VERSION 5.7 ;
BUSBITCHARS "[]" ;
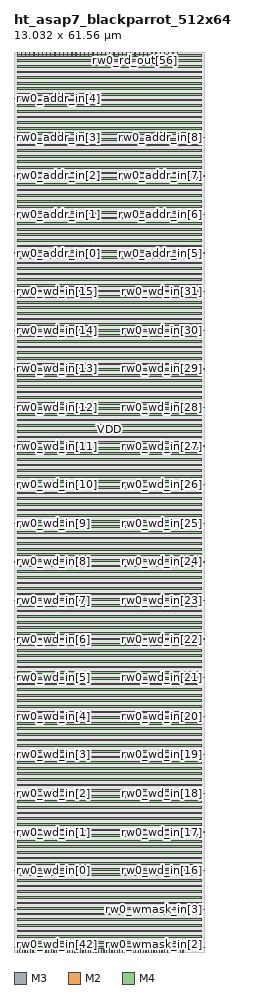
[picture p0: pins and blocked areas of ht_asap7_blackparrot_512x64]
MACRO ht_asap7_blackparrot_512x64
  FOREIGN ht_asap7_blackparrot_512x64 0 0 ;
  SYMMETRY X Y R90 ;
  SIZE 13.032 BY 61.560 ;
  CLASS BLOCK ;
  PIN rw0_wmask_in[0]
    DIRECTION INPUT ;
    USE SIGNAL ;
    SHAPE ABUTMENT ;
    PORT
      LAYER M3 ;
      RECT 0.000 0.276 0.072 0.300 ;
    END
  END rw0_wmask_in[0]
  PIN rw0_wmask_in[1]
    DIRECTION INPUT ;
    USE SIGNAL ;
    SHAPE ABUTMENT ;
    PORT
      LAYER M3 ;
      RECT 0.000 2.916 0.072 2.940 ;
    END
  END rw0_wmask_in[1]
  PIN rw0_wmask_in[2]
    DIRECTION INPUT ;
    USE SIGNAL ;
    SHAPE ABUTMENT ;
    PORT
      LAYER M3 ;
      RECT 12.960 0.276 13.032 0.300 ;
    END
  END rw0_wmask_in[2]
  PIN rw0_wmask_in[3]
    DIRECTION INPUT ;
    USE SIGNAL ;
    SHAPE ABUTMENT ;
    PORT
      LAYER M3 ;
      RECT 12.960 2.916 13.032 2.940 ;
    END
  END rw0_wmask_in[3]
  PIN rw0_wmask_in[4]
    DIRECTION INPUT ;
    USE SIGNAL ;
    SHAPE ABUTMENT ;
    PORT
      LAYER M2 ;
      RECT 0.207 61.290 0.225 61.560 ;
    END
  END rw0_wmask_in[4]
  PIN rw0_wmask_in[5]
    DIRECTION INPUT ;
    USE SIGNAL ;
    SHAPE ABUTMENT ;
    PORT
      LAYER M2 ;
      RECT 0.495 61.290 0.513 61.560 ;
    END
  END rw0_wmask_in[5]
  PIN rw0_wmask_in[6]
    DIRECTION INPUT ;
    USE SIGNAL ;
    SHAPE ABUTMENT ;
    PORT
      LAYER M2 ;
      RECT 0.783 61.290 0.801 61.560 ;
    END
  END rw0_wmask_in[6]
  PIN rw0_wmask_in[7]
    DIRECTION INPUT ;
    USE SIGNAL ;
    SHAPE ABUTMENT ;
    PORT
      LAYER M2 ;
      RECT 1.071 61.290 1.089 61.560 ;
    END
  END rw0_wmask_in[7]
  PIN rw0_wd_in[0]
    DIRECTION INPUT ;
    USE SIGNAL ;
    SHAPE ABUTMENT ;
    PORT
      LAYER M3 ;
      RECT 0.000 5.556 0.072 5.580 ;
    END
  END rw0_wd_in[0]
  PIN rw0_wd_in[1]
    DIRECTION INPUT ;
    USE SIGNAL ;
    SHAPE ABUTMENT ;
    PORT
      LAYER M3 ;
      RECT 0.000 8.196 0.072 8.220 ;
    END
  END rw0_wd_in[1]
  PIN rw0_wd_in[2]
    DIRECTION INPUT ;
    USE SIGNAL ;
    SHAPE ABUTMENT ;
    PORT
      LAYER M3 ;
      RECT 0.000 10.836 0.072 10.860 ;
    END
  END rw0_wd_in[2]
  PIN rw0_wd_in[3]
    DIRECTION INPUT ;
    USE SIGNAL ;
    SHAPE ABUTMENT ;
    PORT
      LAYER M3 ;
      RECT 0.000 13.476 0.072 13.500 ;
    END
  END rw0_wd_in[3]
  PIN rw0_wd_in[4]
    DIRECTION INPUT ;
    USE SIGNAL ;
    SHAPE ABUTMENT ;
    PORT
      LAYER M3 ;
      RECT 0.000 16.116 0.072 16.140 ;
    END
  END rw0_wd_in[4]
  PIN rw0_wd_in[5]
    DIRECTION INPUT ;
    USE SIGNAL ;
    SHAPE ABUTMENT ;
    PORT
      LAYER M3 ;
      RECT 0.000 18.756 0.072 18.780 ;
    END
  END rw0_wd_in[5]
  PIN rw0_wd_in[6]
    DIRECTION INPUT ;
    USE SIGNAL ;
    SHAPE ABUTMENT ;
    PORT
      LAYER M3 ;
      RECT 0.000 21.396 0.072 21.420 ;
    END
  END rw0_wd_in[6]
  PIN rw0_wd_in[7]
    DIRECTION INPUT ;
    USE SIGNAL ;
    SHAPE ABUTMENT ;
    PORT
      LAYER M3 ;
      RECT 0.000 24.036 0.072 24.060 ;
    END
  END rw0_wd_in[7]
  PIN rw0_wd_in[8]
    DIRECTION INPUT ;
    USE SIGNAL ;
    SHAPE ABUTMENT ;
    PORT
      LAYER M3 ;
      RECT 0.000 26.676 0.072 26.700 ;
    END
  END rw0_wd_in[8]
  PIN rw0_wd_in[9]
    DIRECTION INPUT ;
    USE SIGNAL ;
    SHAPE ABUTMENT ;
    PORT
      LAYER M3 ;
      RECT 0.000 29.316 0.072 29.340 ;
    END
  END rw0_wd_in[9]
  PIN rw0_wd_in[10]
    DIRECTION INPUT ;
    USE SIGNAL ;
    SHAPE ABUTMENT ;
    PORT
      LAYER M3 ;
      RECT 0.000 31.956 0.072 31.980 ;
    END
  END rw0_wd_in[10]
  PIN rw0_wd_in[11]
    DIRECTION INPUT ;
    USE SIGNAL ;
    SHAPE ABUTMENT ;
    PORT
      LAYER M3 ;
      RECT 0.000 34.596 0.072 34.620 ;
    END
  END rw0_wd_in[11]
  PIN rw0_wd_in[12]
    DIRECTION INPUT ;
    USE SIGNAL ;
    SHAPE ABUTMENT ;
    PORT
      LAYER M3 ;
      RECT 0.000 37.236 0.072 37.260 ;
    END
  END rw0_wd_in[12]
  PIN rw0_wd_in[13]
    DIRECTION INPUT ;
    USE SIGNAL ;
    SHAPE ABUTMENT ;
    PORT
      LAYER M3 ;
      RECT 0.000 39.876 0.072 39.900 ;
    END
  END rw0_wd_in[13]
  PIN rw0_wd_in[14]
    DIRECTION INPUT ;
    USE SIGNAL ;
    SHAPE ABUTMENT ;
    PORT
      LAYER M3 ;
      RECT 0.000 42.516 0.072 42.540 ;
    END
  END rw0_wd_in[14]
  PIN rw0_wd_in[15]
    DIRECTION INPUT ;
    USE SIGNAL ;
    SHAPE ABUTMENT ;
    PORT
      LAYER M3 ;
      RECT 0.000 45.156 0.072 45.180 ;
    END
  END rw0_wd_in[15]
  PIN rw0_wd_in[16]
    DIRECTION INPUT ;
    USE SIGNAL ;
    SHAPE ABUTMENT ;
    PORT
      LAYER M3 ;
      RECT 12.960 5.556 13.032 5.580 ;
    END
  END rw0_wd_in[16]
  PIN rw0_wd_in[17]
    DIRECTION INPUT ;
    USE SIGNAL ;
    SHAPE ABUTMENT ;
    PORT
      LAYER M3 ;
      RECT 12.960 8.196 13.032 8.220 ;
    END
  END rw0_wd_in[17]
  PIN rw0_wd_in[18]
    DIRECTION INPUT ;
    USE SIGNAL ;
    SHAPE ABUTMENT ;
    PORT
      LAYER M3 ;
      RECT 12.960 10.836 13.032 10.860 ;
    END
  END rw0_wd_in[18]
  PIN rw0_wd_in[19]
    DIRECTION INPUT ;
    USE SIGNAL ;
    SHAPE ABUTMENT ;
    PORT
      LAYER M3 ;
      RECT 12.960 13.476 13.032 13.500 ;
    END
  END rw0_wd_in[19]
  PIN rw0_wd_in[20]
    DIRECTION INPUT ;
    USE SIGNAL ;
    SHAPE ABUTMENT ;
    PORT
      LAYER M3 ;
      RECT 12.960 16.116 13.032 16.140 ;
    END
  END rw0_wd_in[20]
  PIN rw0_wd_in[21]
    DIRECTION INPUT ;
    USE SIGNAL ;
    SHAPE ABUTMENT ;
    PORT
      LAYER M3 ;
      RECT 12.960 18.756 13.032 18.780 ;
    END
  END rw0_wd_in[21]
  PIN rw0_wd_in[22]
    DIRECTION INPUT ;
    USE SIGNAL ;
    SHAPE ABUTMENT ;
    PORT
      LAYER M3 ;
      RECT 12.960 21.396 13.032 21.420 ;
    END
  END rw0_wd_in[22]
  PIN rw0_wd_in[23]
    DIRECTION INPUT ;
    USE SIGNAL ;
    SHAPE ABUTMENT ;
    PORT
      LAYER M3 ;
      RECT 12.960 24.036 13.032 24.060 ;
    END
  END rw0_wd_in[23]
  PIN rw0_wd_in[24]
    DIRECTION INPUT ;
    USE SIGNAL ;
    SHAPE ABUTMENT ;
    PORT
      LAYER M3 ;
      RECT 12.960 26.676 13.032 26.700 ;
    END
  END rw0_wd_in[24]
  PIN rw0_wd_in[25]
    DIRECTION INPUT ;
    USE SIGNAL ;
    SHAPE ABUTMENT ;
    PORT
      LAYER M3 ;
      RECT 12.960 29.316 13.032 29.340 ;
    END
  END rw0_wd_in[25]
  PIN rw0_wd_in[26]
    DIRECTION INPUT ;
    USE SIGNAL ;
    SHAPE ABUTMENT ;
    PORT
      LAYER M3 ;
      RECT 12.960 31.956 13.032 31.980 ;
    END
  END rw0_wd_in[26]
  PIN rw0_wd_in[27]
    DIRECTION INPUT ;
    USE SIGNAL ;
    SHAPE ABUTMENT ;
    PORT
      LAYER M3 ;
      RECT 12.960 34.596 13.032 34.620 ;
    END
  END rw0_wd_in[27]
  PIN rw0_wd_in[28]
    DIRECTION INPUT ;
    USE SIGNAL ;
    SHAPE ABUTMENT ;
    PORT
      LAYER M3 ;
      RECT 12.960 37.236 13.032 37.260 ;
    END
  END rw0_wd_in[28]
  PIN rw0_wd_in[29]
    DIRECTION INPUT ;
    USE SIGNAL ;
    SHAPE ABUTMENT ;
    PORT
      LAYER M3 ;
      RECT 12.960 39.876 13.032 39.900 ;
    END
  END rw0_wd_in[29]
  PIN rw0_wd_in[30]
    DIRECTION INPUT ;
    USE SIGNAL ;
    SHAPE ABUTMENT ;
    PORT
      LAYER M3 ;
      RECT 12.960 42.516 13.032 42.540 ;
    END
  END rw0_wd_in[30]
  PIN rw0_wd_in[31]
    DIRECTION INPUT ;
    USE SIGNAL ;
    SHAPE ABUTMENT ;
    PORT
      LAYER M3 ;
      RECT 12.960 45.156 13.032 45.180 ;
    END
  END rw0_wd_in[31]
  PIN rw0_wd_in[32]
    DIRECTION INPUT ;
    USE SIGNAL ;
    SHAPE ABUTMENT ;
    PORT
      LAYER M2 ;
      RECT 0.207 0.000 0.225 0.270 ;
    END
  END rw0_wd_in[32]
  PIN rw0_wd_in[33]
    DIRECTION INPUT ;
    USE SIGNAL ;
    SHAPE ABUTMENT ;
    PORT
      LAYER M2 ;
      RECT 0.387 0.000 0.405 0.270 ;
    END
  END rw0_wd_in[33]
  PIN rw0_wd_in[34]
    DIRECTION INPUT ;
    USE SIGNAL ;
    SHAPE ABUTMENT ;
    PORT
      LAYER M2 ;
      RECT 0.567 0.000 0.585 0.270 ;
    END
  END rw0_wd_in[34]
  PIN rw0_wd_in[35]
    DIRECTION INPUT ;
    USE SIGNAL ;
    SHAPE ABUTMENT ;
    PORT
      LAYER M2 ;
      RECT 0.747 0.000 0.765 0.270 ;
    END
  END rw0_wd_in[35]
  PIN rw0_wd_in[36]
    DIRECTION INPUT ;
    USE SIGNAL ;
    SHAPE ABUTMENT ;
    PORT
      LAYER M2 ;
      RECT 0.927 0.000 0.945 0.270 ;
    END
  END rw0_wd_in[36]
  PIN rw0_wd_in[37]
    DIRECTION INPUT ;
    USE SIGNAL ;
    SHAPE ABUTMENT ;
    PORT
      LAYER M2 ;
      RECT 1.107 0.000 1.125 0.270 ;
    END
  END rw0_wd_in[37]
  PIN rw0_wd_in[38]
    DIRECTION INPUT ;
    USE SIGNAL ;
    SHAPE ABUTMENT ;
    PORT
      LAYER M2 ;
      RECT 1.287 0.000 1.305 0.270 ;
    END
  END rw0_wd_in[38]
  PIN rw0_wd_in[39]
    DIRECTION INPUT ;
    USE SIGNAL ;
    SHAPE ABUTMENT ;
    PORT
      LAYER M2 ;
      RECT 1.467 0.000 1.485 0.270 ;
    END
  END rw0_wd_in[39]
  PIN rw0_wd_in[40]
    DIRECTION INPUT ;
    USE SIGNAL ;
    SHAPE ABUTMENT ;
    PORT
      LAYER M2 ;
      RECT 1.647 0.000 1.665 0.270 ;
    END
  END rw0_wd_in[40]
  PIN rw0_wd_in[41]
    DIRECTION INPUT ;
    USE SIGNAL ;
    SHAPE ABUTMENT ;
    PORT
      LAYER M2 ;
      RECT 1.827 0.000 1.845 0.270 ;
    END
  END rw0_wd_in[41]
  PIN rw0_wd_in[42]
    DIRECTION INPUT ;
    USE SIGNAL ;
    SHAPE ABUTMENT ;
    PORT
      LAYER M2 ;
      RECT 2.007 0.000 2.025 0.270 ;
    END
  END rw0_wd_in[42]
  PIN rw0_wd_in[43]
    DIRECTION INPUT ;
    USE SIGNAL ;
    SHAPE ABUTMENT ;
    PORT
      LAYER M2 ;
      RECT 2.187 0.000 2.205 0.270 ;
    END
  END rw0_wd_in[43]
  PIN rw0_wd_in[44]
    DIRECTION INPUT ;
    USE SIGNAL ;
    SHAPE ABUTMENT ;
    PORT
      LAYER M2 ;
      RECT 2.367 0.000 2.385 0.270 ;
    END
  END rw0_wd_in[44]
  PIN rw0_wd_in[45]
    DIRECTION INPUT ;
    USE SIGNAL ;
    SHAPE ABUTMENT ;
    PORT
      LAYER M2 ;
      RECT 2.547 0.000 2.565 0.270 ;
    END
  END rw0_wd_in[45]
  PIN rw0_wd_in[46]
    DIRECTION INPUT ;
    USE SIGNAL ;
    SHAPE ABUTMENT ;
    PORT
      LAYER M2 ;
      RECT 2.727 0.000 2.745 0.270 ;
    END
  END rw0_wd_in[46]
  PIN rw0_wd_in[47]
    DIRECTION INPUT ;
    USE SIGNAL ;
    SHAPE ABUTMENT ;
    PORT
      LAYER M2 ;
      RECT 2.907 0.000 2.925 0.270 ;
    END
  END rw0_wd_in[47]
  PIN rw0_wd_in[48]
    DIRECTION INPUT ;
    USE SIGNAL ;
    SHAPE ABUTMENT ;
    PORT
      LAYER M2 ;
      RECT 3.087 0.000 3.105 0.270 ;
    END
  END rw0_wd_in[48]
  PIN rw0_wd_in[49]
    DIRECTION INPUT ;
    USE SIGNAL ;
    SHAPE ABUTMENT ;
    PORT
      LAYER M2 ;
      RECT 3.267 0.000 3.285 0.270 ;
    END
  END rw0_wd_in[49]
  PIN rw0_wd_in[50]
    DIRECTION INPUT ;
    USE SIGNAL ;
    SHAPE ABUTMENT ;
    PORT
      LAYER M2 ;
      RECT 3.447 0.000 3.465 0.270 ;
    END
  END rw0_wd_in[50]
  PIN rw0_wd_in[51]
    DIRECTION INPUT ;
    USE SIGNAL ;
    SHAPE ABUTMENT ;
    PORT
      LAYER M2 ;
      RECT 3.627 0.000 3.645 0.270 ;
    END
  END rw0_wd_in[51]
  PIN rw0_wd_in[52]
    DIRECTION INPUT ;
    USE SIGNAL ;
    SHAPE ABUTMENT ;
    PORT
      LAYER M2 ;
      RECT 3.807 0.000 3.825 0.270 ;
    END
  END rw0_wd_in[52]
  PIN rw0_wd_in[53]
    DIRECTION INPUT ;
    USE SIGNAL ;
    SHAPE ABUTMENT ;
    PORT
      LAYER M2 ;
      RECT 3.987 0.000 4.005 0.270 ;
    END
  END rw0_wd_in[53]
  PIN rw0_wd_in[54]
    DIRECTION INPUT ;
    USE SIGNAL ;
    SHAPE ABUTMENT ;
    PORT
      LAYER M2 ;
      RECT 4.167 0.000 4.185 0.270 ;
    END
  END rw0_wd_in[54]
  PIN rw0_wd_in[55]
    DIRECTION INPUT ;
    USE SIGNAL ;
    SHAPE ABUTMENT ;
    PORT
      LAYER M2 ;
      RECT 4.347 0.000 4.365 0.270 ;
    END
  END rw0_wd_in[55]
  PIN rw0_wd_in[56]
    DIRECTION INPUT ;
    USE SIGNAL ;
    SHAPE ABUTMENT ;
    PORT
      LAYER M2 ;
      RECT 4.527 0.000 4.545 0.270 ;
    END
  END rw0_wd_in[56]
  PIN rw0_wd_in[57]
    DIRECTION INPUT ;
    USE SIGNAL ;
    SHAPE ABUTMENT ;
    PORT
      LAYER M2 ;
      RECT 4.707 0.000 4.725 0.270 ;
    END
  END rw0_wd_in[57]
  PIN rw0_wd_in[58]
    DIRECTION INPUT ;
    USE SIGNAL ;
    SHAPE ABUTMENT ;
    PORT
      LAYER M2 ;
      RECT 4.887 0.000 4.905 0.270 ;
    END
  END rw0_wd_in[58]
  PIN rw0_wd_in[59]
    DIRECTION INPUT ;
    USE SIGNAL ;
    SHAPE ABUTMENT ;
    PORT
      LAYER M2 ;
      RECT 5.067 0.000 5.085 0.270 ;
    END
  END rw0_wd_in[59]
  PIN rw0_wd_in[60]
    DIRECTION INPUT ;
    USE SIGNAL ;
    SHAPE ABUTMENT ;
    PORT
      LAYER M2 ;
      RECT 5.247 0.000 5.265 0.270 ;
    END
  END rw0_wd_in[60]
  PIN rw0_wd_in[61]
    DIRECTION INPUT ;
    USE SIGNAL ;
    SHAPE ABUTMENT ;
    PORT
      LAYER M2 ;
      RECT 5.427 0.000 5.445 0.270 ;
    END
  END rw0_wd_in[61]
  PIN rw0_wd_in[62]
    DIRECTION INPUT ;
    USE SIGNAL ;
    SHAPE ABUTMENT ;
    PORT
      LAYER M2 ;
      RECT 5.607 0.000 5.625 0.270 ;
    END
  END rw0_wd_in[62]
  PIN rw0_wd_in[63]
    DIRECTION INPUT ;
    USE SIGNAL ;
    SHAPE ABUTMENT ;
    PORT
      LAYER M2 ;
      RECT 5.787 0.000 5.805 0.270 ;
    END
  END rw0_wd_in[63]
  PIN rw0_rd_out[0]
    DIRECTION OUTPUT ;
    USE SIGNAL ;
    SHAPE ABUTMENT ;
    PORT
      LAYER M2 ;
      RECT 5.967 0.000 5.985 0.270 ;
    END
  END rw0_rd_out[0]
  PIN rw0_rd_out[1]
    DIRECTION OUTPUT ;
    USE SIGNAL ;
    SHAPE ABUTMENT ;
    PORT
      LAYER M2 ;
      RECT 6.147 0.000 6.165 0.270 ;
    END
  END rw0_rd_out[1]
  PIN rw0_rd_out[2]
    DIRECTION OUTPUT ;
    USE SIGNAL ;
    SHAPE ABUTMENT ;
    PORT
      LAYER M2 ;
      RECT 6.327 0.000 6.345 0.270 ;
    END
  END rw0_rd_out[2]
  PIN rw0_rd_out[3]
    DIRECTION OUTPUT ;
    USE SIGNAL ;
    SHAPE ABUTMENT ;
    PORT
      LAYER M2 ;
      RECT 6.507 0.000 6.525 0.270 ;
    END
  END rw0_rd_out[3]
  PIN rw0_rd_out[4]
    DIRECTION OUTPUT ;
    USE SIGNAL ;
    SHAPE ABUTMENT ;
    PORT
      LAYER M2 ;
      RECT 6.687 0.000 6.705 0.270 ;
    END
  END rw0_rd_out[4]
  PIN rw0_rd_out[5]
    DIRECTION OUTPUT ;
    USE SIGNAL ;
    SHAPE ABUTMENT ;
    PORT
      LAYER M2 ;
      RECT 6.867 0.000 6.885 0.270 ;
    END
  END rw0_rd_out[5]
  PIN rw0_rd_out[6]
    DIRECTION OUTPUT ;
    USE SIGNAL ;
    SHAPE ABUTMENT ;
    PORT
      LAYER M2 ;
      RECT 7.047 0.000 7.065 0.270 ;
    END
  END rw0_rd_out[6]
  PIN rw0_rd_out[7]
    DIRECTION OUTPUT ;
    USE SIGNAL ;
    SHAPE ABUTMENT ;
    PORT
      LAYER M2 ;
      RECT 7.227 0.000 7.245 0.270 ;
    END
  END rw0_rd_out[7]
  PIN rw0_rd_out[8]
    DIRECTION OUTPUT ;
    USE SIGNAL ;
    SHAPE ABUTMENT ;
    PORT
      LAYER M2 ;
      RECT 7.407 0.000 7.425 0.270 ;
    END
  END rw0_rd_out[8]
  PIN rw0_rd_out[9]
    DIRECTION OUTPUT ;
    USE SIGNAL ;
    SHAPE ABUTMENT ;
    PORT
      LAYER M2 ;
      RECT 7.587 0.000 7.605 0.270 ;
    END
  END rw0_rd_out[9]
  PIN rw0_rd_out[10]
    DIRECTION OUTPUT ;
    USE SIGNAL ;
    SHAPE ABUTMENT ;
    PORT
      LAYER M2 ;
      RECT 7.767 0.000 7.785 0.270 ;
    END
  END rw0_rd_out[10]
  PIN rw0_rd_out[11]
    DIRECTION OUTPUT ;
    USE SIGNAL ;
    SHAPE ABUTMENT ;
    PORT
      LAYER M2 ;
      RECT 7.947 0.000 7.965 0.270 ;
    END
  END rw0_rd_out[11]
  PIN rw0_rd_out[12]
    DIRECTION OUTPUT ;
    USE SIGNAL ;
    SHAPE ABUTMENT ;
    PORT
      LAYER M2 ;
      RECT 8.127 0.000 8.145 0.270 ;
    END
  END rw0_rd_out[12]
  PIN rw0_rd_out[13]
    DIRECTION OUTPUT ;
    USE SIGNAL ;
    SHAPE ABUTMENT ;
    PORT
      LAYER M2 ;
      RECT 8.307 0.000 8.325 0.270 ;
    END
  END rw0_rd_out[13]
  PIN rw0_rd_out[14]
    DIRECTION OUTPUT ;
    USE SIGNAL ;
    SHAPE ABUTMENT ;
    PORT
      LAYER M2 ;
      RECT 8.487 0.000 8.505 0.270 ;
    END
  END rw0_rd_out[14]
  PIN rw0_rd_out[15]
    DIRECTION OUTPUT ;
    USE SIGNAL ;
    SHAPE ABUTMENT ;
    PORT
      LAYER M2 ;
      RECT 8.667 0.000 8.685 0.270 ;
    END
  END rw0_rd_out[15]
  PIN rw0_rd_out[16]
    DIRECTION OUTPUT ;
    USE SIGNAL ;
    SHAPE ABUTMENT ;
    PORT
      LAYER M2 ;
      RECT 8.847 0.000 8.865 0.270 ;
    END
  END rw0_rd_out[16]
  PIN rw0_rd_out[17]
    DIRECTION OUTPUT ;
    USE SIGNAL ;
    SHAPE ABUTMENT ;
    PORT
      LAYER M2 ;
      RECT 9.027 0.000 9.045 0.270 ;
    END
  END rw0_rd_out[17]
  PIN rw0_rd_out[18]
    DIRECTION OUTPUT ;
    USE SIGNAL ;
    SHAPE ABUTMENT ;
    PORT
      LAYER M2 ;
      RECT 9.207 0.000 9.225 0.270 ;
    END
  END rw0_rd_out[18]
  PIN rw0_rd_out[19]
    DIRECTION OUTPUT ;
    USE SIGNAL ;
    SHAPE ABUTMENT ;
    PORT
      LAYER M2 ;
      RECT 9.387 0.000 9.405 0.270 ;
    END
  END rw0_rd_out[19]
  PIN rw0_rd_out[20]
    DIRECTION OUTPUT ;
    USE SIGNAL ;
    SHAPE ABUTMENT ;
    PORT
      LAYER M2 ;
      RECT 9.567 0.000 9.585 0.270 ;
    END
  END rw0_rd_out[20]
  PIN rw0_rd_out[21]
    DIRECTION OUTPUT ;
    USE SIGNAL ;
    SHAPE ABUTMENT ;
    PORT
      LAYER M2 ;
      RECT 9.747 0.000 9.765 0.270 ;
    END
  END rw0_rd_out[21]
  PIN rw0_rd_out[22]
    DIRECTION OUTPUT ;
    USE SIGNAL ;
    SHAPE ABUTMENT ;
    PORT
      LAYER M2 ;
      RECT 9.927 0.000 9.945 0.270 ;
    END
  END rw0_rd_out[22]
  PIN rw0_rd_out[23]
    DIRECTION OUTPUT ;
    USE SIGNAL ;
    SHAPE ABUTMENT ;
    PORT
      LAYER M2 ;
      RECT 10.107 0.000 10.125 0.270 ;
    END
  END rw0_rd_out[23]
  PIN rw0_rd_out[24]
    DIRECTION OUTPUT ;
    USE SIGNAL ;
    SHAPE ABUTMENT ;
    PORT
      LAYER M2 ;
      RECT 10.287 0.000 10.305 0.270 ;
    END
  END rw0_rd_out[24]
  PIN rw0_rd_out[25]
    DIRECTION OUTPUT ;
    USE SIGNAL ;
    SHAPE ABUTMENT ;
    PORT
      LAYER M2 ;
      RECT 10.467 0.000 10.485 0.270 ;
    END
  END rw0_rd_out[25]
  PIN rw0_rd_out[26]
    DIRECTION OUTPUT ;
    USE SIGNAL ;
    SHAPE ABUTMENT ;
    PORT
      LAYER M2 ;
      RECT 10.647 0.000 10.665 0.270 ;
    END
  END rw0_rd_out[26]
  PIN rw0_rd_out[27]
    DIRECTION OUTPUT ;
    USE SIGNAL ;
    SHAPE ABUTMENT ;
    PORT
      LAYER M2 ;
      RECT 10.827 0.000 10.845 0.270 ;
    END
  END rw0_rd_out[27]
  PIN rw0_rd_out[28]
    DIRECTION OUTPUT ;
    USE SIGNAL ;
    SHAPE ABUTMENT ;
    PORT
      LAYER M2 ;
      RECT 11.007 0.000 11.025 0.270 ;
    END
  END rw0_rd_out[28]
  PIN rw0_rd_out[29]
    DIRECTION OUTPUT ;
    USE SIGNAL ;
    SHAPE ABUTMENT ;
    PORT
      LAYER M2 ;
      RECT 11.187 0.000 11.205 0.270 ;
    END
  END rw0_rd_out[29]
  PIN rw0_rd_out[30]
    DIRECTION OUTPUT ;
    USE SIGNAL ;
    SHAPE ABUTMENT ;
    PORT
      LAYER M2 ;
      RECT 11.367 0.000 11.385 0.270 ;
    END
  END rw0_rd_out[30]
  PIN rw0_rd_out[31]
    DIRECTION OUTPUT ;
    USE SIGNAL ;
    SHAPE ABUTMENT ;
    PORT
      LAYER M2 ;
      RECT 11.547 0.000 11.565 0.270 ;
    END
  END rw0_rd_out[31]
  PIN rw0_rd_out[32]
    DIRECTION OUTPUT ;
    USE SIGNAL ;
    SHAPE ABUTMENT ;
    PORT
      LAYER M2 ;
      RECT 1.359 61.290 1.377 61.560 ;
    END
  END rw0_rd_out[32]
  PIN rw0_rd_out[33]
    DIRECTION OUTPUT ;
    USE SIGNAL ;
    SHAPE ABUTMENT ;
    PORT
      LAYER M2 ;
      RECT 1.647 61.290 1.665 61.560 ;
    END
  END rw0_rd_out[33]
  PIN rw0_rd_out[34]
    DIRECTION OUTPUT ;
    USE SIGNAL ;
    SHAPE ABUTMENT ;
    PORT
      LAYER M2 ;
      RECT 1.935 61.290 1.953 61.560 ;
    END
  END rw0_rd_out[34]
  PIN rw0_rd_out[35]
    DIRECTION OUTPUT ;
    USE SIGNAL ;
    SHAPE ABUTMENT ;
    PORT
      LAYER M2 ;
      RECT 2.223 61.290 2.241 61.560 ;
    END
  END rw0_rd_out[35]
  PIN rw0_rd_out[36]
    DIRECTION OUTPUT ;
    USE SIGNAL ;
    SHAPE ABUTMENT ;
    PORT
      LAYER M2 ;
      RECT 2.511 61.290 2.529 61.560 ;
    END
  END rw0_rd_out[36]
  PIN rw0_rd_out[37]
    DIRECTION OUTPUT ;
    USE SIGNAL ;
    SHAPE ABUTMENT ;
    PORT
      LAYER M2 ;
      RECT 2.799 61.290 2.817 61.560 ;
    END
  END rw0_rd_out[37]
  PIN rw0_rd_out[38]
    DIRECTION OUTPUT ;
    USE SIGNAL ;
    SHAPE ABUTMENT ;
    PORT
      LAYER M2 ;
      RECT 3.087 61.290 3.105 61.560 ;
    END
  END rw0_rd_out[38]
  PIN rw0_rd_out[39]
    DIRECTION OUTPUT ;
    USE SIGNAL ;
    SHAPE ABUTMENT ;
    PORT
      LAYER M2 ;
      RECT 3.375 61.290 3.393 61.560 ;
    END
  END rw0_rd_out[39]
  PIN rw0_rd_out[40]
    DIRECTION OUTPUT ;
    USE SIGNAL ;
    SHAPE ABUTMENT ;
    PORT
      LAYER M2 ;
      RECT 3.663 61.290 3.681 61.560 ;
    END
  END rw0_rd_out[40]
  PIN rw0_rd_out[41]
    DIRECTION OUTPUT ;
    USE SIGNAL ;
    SHAPE ABUTMENT ;
    PORT
      LAYER M2 ;
      RECT 3.951 61.290 3.969 61.560 ;
    END
  END rw0_rd_out[41]
  PIN rw0_rd_out[42]
    DIRECTION OUTPUT ;
    USE SIGNAL ;
    SHAPE ABUTMENT ;
    PORT
      LAYER M2 ;
      RECT 4.239 61.290 4.257 61.560 ;
    END
  END rw0_rd_out[42]
  PIN rw0_rd_out[43]
    DIRECTION OUTPUT ;
    USE SIGNAL ;
    SHAPE ABUTMENT ;
    PORT
      LAYER M2 ;
      RECT 4.527 61.290 4.545 61.560 ;
    END
  END rw0_rd_out[43]
  PIN rw0_rd_out[44]
    DIRECTION OUTPUT ;
    USE SIGNAL ;
    SHAPE ABUTMENT ;
    PORT
      LAYER M2 ;
      RECT 4.815 61.290 4.833 61.560 ;
    END
  END rw0_rd_out[44]
  PIN rw0_rd_out[45]
    DIRECTION OUTPUT ;
    USE SIGNAL ;
    SHAPE ABUTMENT ;
    PORT
      LAYER M2 ;
      RECT 5.103 61.290 5.121 61.560 ;
    END
  END rw0_rd_out[45]
  PIN rw0_rd_out[46]
    DIRECTION OUTPUT ;
    USE SIGNAL ;
    SHAPE ABUTMENT ;
    PORT
      LAYER M2 ;
      RECT 5.391 61.290 5.409 61.560 ;
    END
  END rw0_rd_out[46]
  PIN rw0_rd_out[47]
    DIRECTION OUTPUT ;
    USE SIGNAL ;
    SHAPE ABUTMENT ;
    PORT
      LAYER M2 ;
      RECT 5.679 61.290 5.697 61.560 ;
    END
  END rw0_rd_out[47]
  PIN rw0_rd_out[48]
    DIRECTION OUTPUT ;
    USE SIGNAL ;
    SHAPE ABUTMENT ;
    PORT
      LAYER M2 ;
      RECT 5.967 61.290 5.985 61.560 ;
    END
  END rw0_rd_out[48]
  PIN rw0_rd_out[49]
    DIRECTION OUTPUT ;
    USE SIGNAL ;
    SHAPE ABUTMENT ;
    PORT
      LAYER M2 ;
      RECT 6.255 61.290 6.273 61.560 ;
    END
  END rw0_rd_out[49]
  PIN rw0_rd_out[50]
    DIRECTION OUTPUT ;
    USE SIGNAL ;
    SHAPE ABUTMENT ;
    PORT
      LAYER M2 ;
      RECT 6.543 61.290 6.561 61.560 ;
    END
  END rw0_rd_out[50]
  PIN rw0_rd_out[51]
    DIRECTION OUTPUT ;
    USE SIGNAL ;
    SHAPE ABUTMENT ;
    PORT
      LAYER M2 ;
      RECT 6.831 61.290 6.849 61.560 ;
    END
  END rw0_rd_out[51]
  PIN rw0_rd_out[52]
    DIRECTION OUTPUT ;
    USE SIGNAL ;
    SHAPE ABUTMENT ;
    PORT
      LAYER M2 ;
      RECT 7.119 61.290 7.137 61.560 ;
    END
  END rw0_rd_out[52]
  PIN rw0_rd_out[53]
    DIRECTION OUTPUT ;
    USE SIGNAL ;
    SHAPE ABUTMENT ;
    PORT
      LAYER M2 ;
      RECT 7.407 61.290 7.425 61.560 ;
    END
  END rw0_rd_out[53]
  PIN rw0_rd_out[54]
    DIRECTION OUTPUT ;
    USE SIGNAL ;
    SHAPE ABUTMENT ;
    PORT
      LAYER M2 ;
      RECT 7.695 61.290 7.713 61.560 ;
    END
  END rw0_rd_out[54]
  PIN rw0_rd_out[55]
    DIRECTION OUTPUT ;
    USE SIGNAL ;
    SHAPE ABUTMENT ;
    PORT
      LAYER M2 ;
      RECT 7.983 61.290 8.001 61.560 ;
    END
  END rw0_rd_out[55]
  PIN rw0_rd_out[56]
    DIRECTION OUTPUT ;
    USE SIGNAL ;
    SHAPE ABUTMENT ;
    PORT
      LAYER M2 ;
      RECT 8.271 61.290 8.289 61.560 ;
    END
  END rw0_rd_out[56]
  PIN rw0_rd_out[57]
    DIRECTION OUTPUT ;
    USE SIGNAL ;
    SHAPE ABUTMENT ;
    PORT
      LAYER M2 ;
      RECT 8.559 61.290 8.577 61.560 ;
    END
  END rw0_rd_out[57]
  PIN rw0_rd_out[58]
    DIRECTION OUTPUT ;
    USE SIGNAL ;
    SHAPE ABUTMENT ;
    PORT
      LAYER M2 ;
      RECT 8.847 61.290 8.865 61.560 ;
    END
  END rw0_rd_out[58]
  PIN rw0_rd_out[59]
    DIRECTION OUTPUT ;
    USE SIGNAL ;
    SHAPE ABUTMENT ;
    PORT
      LAYER M2 ;
      RECT 9.135 61.290 9.153 61.560 ;
    END
  END rw0_rd_out[59]
  PIN rw0_rd_out[60]
    DIRECTION OUTPUT ;
    USE SIGNAL ;
    SHAPE ABUTMENT ;
    PORT
      LAYER M2 ;
      RECT 9.423 61.290 9.441 61.560 ;
    END
  END rw0_rd_out[60]
  PIN rw0_rd_out[61]
    DIRECTION OUTPUT ;
    USE SIGNAL ;
    SHAPE ABUTMENT ;
    PORT
      LAYER M2 ;
      RECT 9.711 61.290 9.729 61.560 ;
    END
  END rw0_rd_out[61]
  PIN rw0_rd_out[62]
    DIRECTION OUTPUT ;
    USE SIGNAL ;
    SHAPE ABUTMENT ;
    PORT
      LAYER M2 ;
      RECT 9.999 61.290 10.017 61.560 ;
    END
  END rw0_rd_out[62]
  PIN rw0_rd_out[63]
    DIRECTION OUTPUT ;
    USE SIGNAL ;
    SHAPE ABUTMENT ;
    PORT
      LAYER M2 ;
      RECT 10.287 61.290 10.305 61.560 ;
    END
  END rw0_rd_out[63]
  PIN rw0_addr_in[0]
    DIRECTION INPUT ;
    USE SIGNAL ;
    SHAPE ABUTMENT ;
    PORT
      LAYER M3 ;
      RECT 0.000 47.796 0.072 47.820 ;
    END
  END rw0_addr_in[0]
  PIN rw0_addr_in[1]
    DIRECTION INPUT ;
    USE SIGNAL ;
    SHAPE ABUTMENT ;
    PORT
      LAYER M3 ;
      RECT 0.000 50.436 0.072 50.460 ;
    END
  END rw0_addr_in[1]
  PIN rw0_addr_in[2]
    DIRECTION INPUT ;
    USE SIGNAL ;
    SHAPE ABUTMENT ;
    PORT
      LAYER M3 ;
      RECT 0.000 53.076 0.072 53.100 ;
    END
  END rw0_addr_in[2]
  PIN rw0_addr_in[3]
    DIRECTION INPUT ;
    USE SIGNAL ;
    SHAPE ABUTMENT ;
    PORT
      LAYER M3 ;
      RECT 0.000 55.716 0.072 55.740 ;
    END
  END rw0_addr_in[3]
  PIN rw0_addr_in[4]
    DIRECTION INPUT ;
    USE SIGNAL ;
    SHAPE ABUTMENT ;
    PORT
      LAYER M3 ;
      RECT 0.000 58.356 0.072 58.380 ;
    END
  END rw0_addr_in[4]
  PIN rw0_addr_in[5]
    DIRECTION INPUT ;
    USE SIGNAL ;
    SHAPE ABUTMENT ;
    PORT
      LAYER M3 ;
      RECT 12.960 47.796 13.032 47.820 ;
    END
  END rw0_addr_in[5]
  PIN rw0_addr_in[6]
    DIRECTION INPUT ;
    USE SIGNAL ;
    SHAPE ABUTMENT ;
    PORT
      LAYER M3 ;
      RECT 12.960 50.436 13.032 50.460 ;
    END
  END rw0_addr_in[6]
  PIN rw0_addr_in[7]
    DIRECTION INPUT ;
    USE SIGNAL ;
    SHAPE ABUTMENT ;
    PORT
      LAYER M3 ;
      RECT 12.960 53.076 13.032 53.100 ;
    END
  END rw0_addr_in[7]
  PIN rw0_addr_in[8]
    DIRECTION INPUT ;
    USE SIGNAL ;
    SHAPE ABUTMENT ;
    PORT
      LAYER M3 ;
      RECT 12.960 55.716 13.032 55.740 ;
    END
  END rw0_addr_in[8]
  PIN rw0_we_in
    DIRECTION INPUT ;
    USE SIGNAL ;
    SHAPE ABUTMENT ;
    PORT
      LAYER M2 ;
      RECT 10.575 61.290 10.593 61.560 ;
    END
  END rw0_we_in
  PIN rw0_ce_in
    DIRECTION INPUT ;
    USE SIGNAL ;
    SHAPE ABUTMENT ;
    PORT
      LAYER M2 ;
      RECT 10.863 61.290 10.881 61.560 ;
    END
  END rw0_ce_in
  PIN rw0_clk
    DIRECTION INPUT ;
    USE SIGNAL ;
    SHAPE ABUTMENT ;
    PORT
      LAYER M2 ;
      RECT 11.151 61.290 11.169 61.560 ;
    END
  END rw0_clk
  PIN VSS
    DIRECTION INOUT ;
    USE GROUND ;
    PORT
      LAYER M4 ;
      RECT 0.216 0.228 12.816 0.348 ;
      RECT 0.216 0.996 12.816 1.116 ;
      RECT 0.216 1.764 12.816 1.884 ;
      RECT 0.216 2.532 12.816 2.652 ;
      RECT 0.216 3.300 12.816 3.420 ;
      RECT 0.216 4.068 12.816 4.188 ;
      RECT 0.216 4.836 12.816 4.956 ;
      RECT 0.216 5.604 12.816 5.724 ;
      RECT 0.216 6.372 12.816 6.492 ;
      RECT 0.216 7.140 12.816 7.260 ;
      RECT 0.216 7.908 12.816 8.028 ;
      RECT 0.216 8.676 12.816 8.796 ;
      RECT 0.216 9.444 12.816 9.564 ;
      RECT 0.216 10.212 12.816 10.332 ;
      RECT 0.216 10.980 12.816 11.100 ;
      RECT 0.216 11.748 12.816 11.868 ;
      RECT 0.216 12.516 12.816 12.636 ;
      RECT 0.216 13.284 12.816 13.404 ;
      RECT 0.216 14.052 12.816 14.172 ;
      RECT 0.216 14.820 12.816 14.940 ;
      RECT 0.216 15.588 12.816 15.708 ;
      RECT 0.216 16.356 12.816 16.476 ;
      RECT 0.216 17.124 12.816 17.244 ;
      RECT 0.216 17.892 12.816 18.012 ;
      RECT 0.216 18.660 12.816 18.780 ;
      RECT 0.216 19.428 12.816 19.548 ;
      RECT 0.216 20.196 12.816 20.316 ;
      RECT 0.216 20.964 12.816 21.084 ;
      RECT 0.216 21.732 12.816 21.852 ;
      RECT 0.216 22.500 12.816 22.620 ;
      RECT 0.216 23.268 12.816 23.388 ;
      RECT 0.216 24.036 12.816 24.156 ;
      RECT 0.216 24.804 12.816 24.924 ;
      RECT 0.216 25.572 12.816 25.692 ;
      RECT 0.216 26.340 12.816 26.460 ;
      RECT 0.216 27.108 12.816 27.228 ;
      RECT 0.216 27.876 12.816 27.996 ;
      RECT 0.216 28.644 12.816 28.764 ;
      RECT 0.216 29.412 12.816 29.532 ;
      RECT 0.216 30.180 12.816 30.300 ;
      RECT 0.216 30.948 12.816 31.068 ;
      RECT 0.216 31.716 12.816 31.836 ;
      RECT 0.216 32.484 12.816 32.604 ;
      RECT 0.216 33.252 12.816 33.372 ;
      RECT 0.216 34.020 12.816 34.140 ;
      RECT 0.216 34.788 12.816 34.908 ;
      RECT 0.216 35.556 12.816 35.676 ;
      RECT 0.216 36.324 12.816 36.444 ;
      RECT 0.216 37.092 12.816 37.212 ;
      RECT 0.216 37.860 12.816 37.980 ;
      RECT 0.216 38.628 12.816 38.748 ;
      RECT 0.216 39.396 12.816 39.516 ;
      RECT 0.216 40.164 12.816 40.284 ;
      RECT 0.216 40.932 12.816 41.052 ;
      RECT 0.216 41.700 12.816 41.820 ;
      RECT 0.216 42.468 12.816 42.588 ;
      RECT 0.216 43.236 12.816 43.356 ;
      RECT 0.216 44.004 12.816 44.124 ;
      RECT 0.216 44.772 12.816 44.892 ;
      RECT 0.216 45.540 12.816 45.660 ;
      RECT 0.216 46.308 12.816 46.428 ;
      RECT 0.216 47.076 12.816 47.196 ;
      RECT 0.216 47.844 12.816 47.964 ;
      RECT 0.216 48.612 12.816 48.732 ;
      RECT 0.216 49.380 12.816 49.500 ;
      RECT 0.216 50.148 12.816 50.268 ;
      RECT 0.216 50.916 12.816 51.036 ;
      RECT 0.216 51.684 12.816 51.804 ;
      RECT 0.216 52.452 12.816 52.572 ;
      RECT 0.216 53.220 12.816 53.340 ;
      RECT 0.216 53.988 12.816 54.108 ;
      RECT 0.216 54.756 12.816 54.876 ;
      RECT 0.216 55.524 12.816 55.644 ;
      RECT 0.216 56.292 12.816 56.412 ;
      RECT 0.216 57.060 12.816 57.180 ;
      RECT 0.216 57.828 12.816 57.948 ;
      RECT 0.216 58.596 12.816 58.716 ;
      RECT 0.216 59.364 12.816 59.484 ;
      RECT 0.216 60.132 12.816 60.252 ;
      RECT 0.216 60.900 12.816 61.020 ;
    END
  END VSS
  PIN VDD
    DIRECTION INOUT ;
    USE POWER ;
    PORT
      LAYER M4 ;
      RECT 0.216 0.612 12.816 0.732 ;
      RECT 0.216 1.380 12.816 1.500 ;
      RECT 0.216 2.148 12.816 2.268 ;
      RECT 0.216 2.916 12.816 3.036 ;
      RECT 0.216 3.684 12.816 3.804 ;
      RECT 0.216 4.452 12.816 4.572 ;
      RECT 0.216 5.220 12.816 5.340 ;
      RECT 0.216 5.988 12.816 6.108 ;
      RECT 0.216 6.756 12.816 6.876 ;
      RECT 0.216 7.524 12.816 7.644 ;
      RECT 0.216 8.292 12.816 8.412 ;
      RECT 0.216 9.060 12.816 9.180 ;
      RECT 0.216 9.828 12.816 9.948 ;
      RECT 0.216 10.596 12.816 10.716 ;
      RECT 0.216 11.364 12.816 11.484 ;
      RECT 0.216 12.132 12.816 12.252 ;
      RECT 0.216 12.900 12.816 13.020 ;
      RECT 0.216 13.668 12.816 13.788 ;
      RECT 0.216 14.436 12.816 14.556 ;
      RECT 0.216 15.204 12.816 15.324 ;
      RECT 0.216 15.972 12.816 16.092 ;
      RECT 0.216 16.740 12.816 16.860 ;
      RECT 0.216 17.508 12.816 17.628 ;
      RECT 0.216 18.276 12.816 18.396 ;
      RECT 0.216 19.044 12.816 19.164 ;
      RECT 0.216 19.812 12.816 19.932 ;
      RECT 0.216 20.580 12.816 20.700 ;
      RECT 0.216 21.348 12.816 21.468 ;
      RECT 0.216 22.116 12.816 22.236 ;
      RECT 0.216 22.884 12.816 23.004 ;
      RECT 0.216 23.652 12.816 23.772 ;
      RECT 0.216 24.420 12.816 24.540 ;
      RECT 0.216 25.188 12.816 25.308 ;
      RECT 0.216 25.956 12.816 26.076 ;
      RECT 0.216 26.724 12.816 26.844 ;
      RECT 0.216 27.492 12.816 27.612 ;
      RECT 0.216 28.260 12.816 28.380 ;
      RECT 0.216 29.028 12.816 29.148 ;
      RECT 0.216 29.796 12.816 29.916 ;
      RECT 0.216 30.564 12.816 30.684 ;
      RECT 0.216 31.332 12.816 31.452 ;
      RECT 0.216 32.100 12.816 32.220 ;
      RECT 0.216 32.868 12.816 32.988 ;
      RECT 0.216 33.636 12.816 33.756 ;
      RECT 0.216 34.404 12.816 34.524 ;
      RECT 0.216 35.172 12.816 35.292 ;
      RECT 0.216 35.940 12.816 36.060 ;
      RECT 0.216 36.708 12.816 36.828 ;
      RECT 0.216 37.476 12.816 37.596 ;
      RECT 0.216 38.244 12.816 38.364 ;
      RECT 0.216 39.012 12.816 39.132 ;
      RECT 0.216 39.780 12.816 39.900 ;
      RECT 0.216 40.548 12.816 40.668 ;
      RECT 0.216 41.316 12.816 41.436 ;
      RECT 0.216 42.084 12.816 42.204 ;
      RECT 0.216 42.852 12.816 42.972 ;
      RECT 0.216 43.620 12.816 43.740 ;
      RECT 0.216 44.388 12.816 44.508 ;
      RECT 0.216 45.156 12.816 45.276 ;
      RECT 0.216 45.924 12.816 46.044 ;
      RECT 0.216 46.692 12.816 46.812 ;
      RECT 0.216 47.460 12.816 47.580 ;
      RECT 0.216 48.228 12.816 48.348 ;
      RECT 0.216 48.996 12.816 49.116 ;
      RECT 0.216 49.764 12.816 49.884 ;
      RECT 0.216 50.532 12.816 50.652 ;
      RECT 0.216 51.300 12.816 51.420 ;
      RECT 0.216 52.068 12.816 52.188 ;
      RECT 0.216 52.836 12.816 52.956 ;
      RECT 0.216 53.604 12.816 53.724 ;
      RECT 0.216 54.372 12.816 54.492 ;
      RECT 0.216 55.140 12.816 55.260 ;
      RECT 0.216 55.908 12.816 56.028 ;
      RECT 0.216 56.676 12.816 56.796 ;
      RECT 0.216 57.444 12.816 57.564 ;
      RECT 0.216 58.212 12.816 58.332 ;
      RECT 0.216 58.980 12.816 59.100 ;
      RECT 0.216 59.748 12.816 59.868 ;
      RECT 0.216 60.516 12.816 60.636 ;
      RECT 0.216 61.284 12.816 61.404 ;
    END
  END VDD
  OBS
    LAYER M1 ;
    RECT 0 0 13.032 61.560 ;
    LAYER M2 ;
    RECT 0 0 13.032 61.560 ;
    LAYER M3 ;
    RECT 0 0 13.032 61.560 ;
    LAYER M4 ;
    RECT 0 0 13.032 61.560 ;
  END
END ht_asap7_blackparrot_512x64

END LIBRARY
